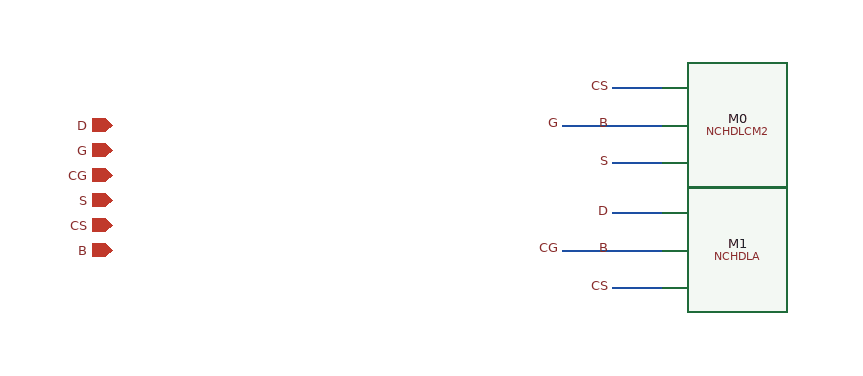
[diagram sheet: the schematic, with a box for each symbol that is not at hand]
v {xschem version=3.0.0 file_version=1.2 }
C {devices/iopin.sym} 0 0 0 0{name=p0 lab=D}
C {devices/iopin.sym} 0 20 0 0{name=p1 lab=G}
C {devices/iopin.sym} 0 40 0 0{name=p2 lab=CG}
C {devices/iopin.sym} 0 60 0 0{name=p3 lab=S}
C {devices/iopin.sym} 0 80 0 0{name=p4 lab=CS}
C {devices/iopin.sym} 0 100 0 0{name=p5 lab=B}
C {SUN_TR_SK130NM/NCHDLCM2.sym} 400 0 0 0 {name=M0}
N 400.0 -30.0 440.0 -30.0{lab=CS}
C {devices/lab_pin.sym} 400.0 -30.0 0 0  {name=l0 sig_type=std_logic lab=CS }
N 360.0 0.0 400.0 0.0{lab=G}
C {devices/lab_pin.sym} 360.0 0.0 0 0  {name=l1 sig_type=std_logic lab=G }
N 400.0 30.0 440.0 30.0{lab=S}
C {devices/lab_pin.sym} 400.0 30.0 0 0  {name=l2 sig_type=std_logic lab=S }
N 400.0 0.0 440.0 0.0{lab=B}
C {devices/lab_pin.sym} 400.0 0.0 0 0  {name=l3 sig_type=std_logic lab=B }
C {SUN_TR_SK130NM/NCHDLA.sym} 400 100 0 0 {name=M1}
N 400.0 70.0 440.0 70.0{lab=D}
C {devices/lab_pin.sym} 400.0 70.0 0 0  {name=l4 sig_type=std_logic lab=D }
N 360.0 100.0 400.0 100.0{lab=CG}
C {devices/lab_pin.sym} 360.0 100.0 0 0  {name=l5 sig_type=std_logic lab=CG }
N 400.0 130.0 440.0 130.0{lab=CS}
C {devices/lab_pin.sym} 400.0 130.0 0 0  {name=l6 sig_type=std_logic lab=CS }
N 400.0 100.0 440.0 100.0{lab=B}
C {devices/lab_pin.sym} 400.0 100.0 0 0  {name=l7 sig_type=std_logic lab=B }
